VERSION 5.8 ;
BUSBITCHARS "[]" ;

UNITS
  DATABASE MICRONS 2000 ;
END UNITS

PROPERTYDEFINITIONS
  MACRO expanded_util REAL ;
END PROPERTYDEFINITIONS

LAYER OVERLAP
  TYPE OVERLAP ;
END OVERLAP

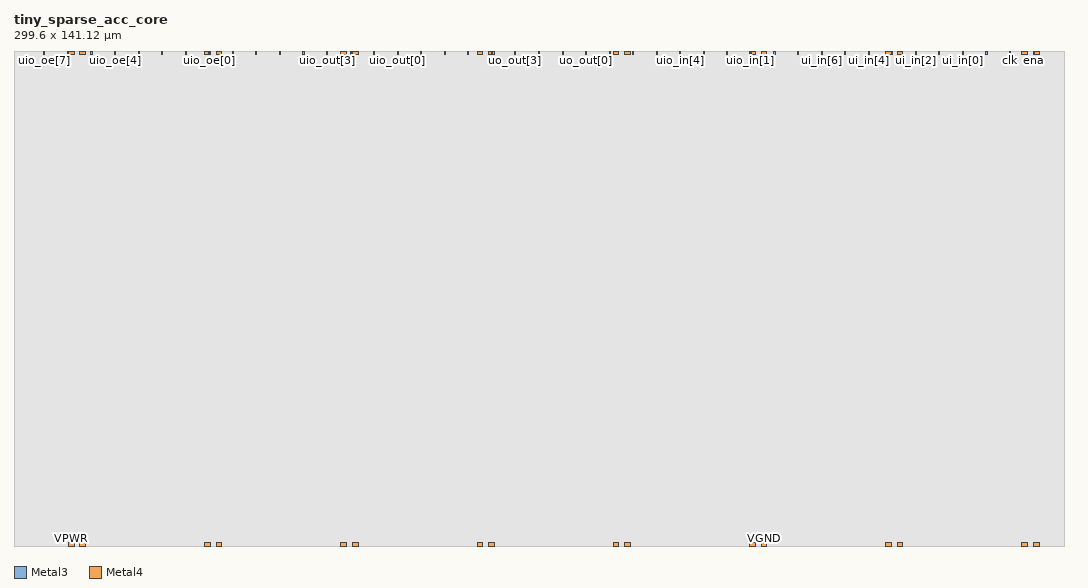
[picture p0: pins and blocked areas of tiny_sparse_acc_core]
MACRO tiny_sparse_acc_core
  CLASS BLOCK ;
  ORIGIN 0 0 ;
  SIZE 299.6 BY 141.12 ;
  SYMMETRY X Y ;
  PIN ui_in[7]
    DIRECTION INPUT ;
    USE SIGNAL ;
    PORT
      LAYER Metal3 ;
        RECT 223.57 140.12 223.87 141.12 ;
    END
  END ui_in[7]
  PIN ui_in[6]
    DIRECTION INPUT ;
    USE SIGNAL ;
    PORT
      LAYER Metal3 ;
        RECT 230.29 140.12 230.59 141.12 ;
    END
  END ui_in[6]
  PIN ui_in[5]
    DIRECTION INPUT ;
    USE SIGNAL ;
    PORT
      LAYER Metal3 ;
        RECT 237.01 140.12 237.31 141.12 ;
    END
  END ui_in[5]
  PIN ui_in[4]
    DIRECTION INPUT ;
    USE SIGNAL ;
    PORT
      LAYER Metal3 ;
        RECT 243.73 140.12 244.03 141.12 ;
    END
  END ui_in[4]
  PIN ui_in[3]
    DIRECTION INPUT ;
    USE SIGNAL ;
    PORT
      LAYER Metal3 ;
        RECT 250.45 140.12 250.75 141.12 ;
    END
  END ui_in[3]
  PIN ui_in[2]
    DIRECTION INPUT ;
    USE SIGNAL ;
    PORT
      LAYER Metal3 ;
        RECT 257.17 140.12 257.47 141.12 ;
    END
  END ui_in[2]
  PIN ui_in[1]
    DIRECTION INPUT ;
    USE SIGNAL ;
    PORT
      LAYER Metal3 ;
        RECT 263.89 140.12 264.19 141.12 ;
    END
  END ui_in[1]
  PIN ui_in[0]
    DIRECTION INPUT ;
    USE SIGNAL ;
    PORT
      LAYER Metal3 ;
        RECT 270.61 140.12 270.91 141.12 ;
    END
  END ui_in[0]
  PIN uo_out[7]
    DIRECTION OUTPUT ;
    USE SIGNAL ;
    PORT
      LAYER Metal3 ;
        RECT 116.05 140.12 116.35 141.12 ;
    END
  END uo_out[7]
  PIN uo_out[6]
    DIRECTION OUTPUT ;
    USE SIGNAL ;
    PORT
      LAYER Metal3 ;
        RECT 122.77 140.12 123.07 141.12 ;
    END
  END uo_out[6]
  PIN uo_out[5]
    DIRECTION OUTPUT ;
    USE SIGNAL ;
    PORT
      LAYER Metal3 ;
        RECT 129.49 140.12 129.79 141.12 ;
    END
  END uo_out[5]
  PIN uo_out[4]
    DIRECTION OUTPUT ;
    USE SIGNAL ;
    PORT
      LAYER Metal3 ;
        RECT 136.21 140.12 136.51 141.12 ;
    END
  END uo_out[4]
  PIN uo_out[3]
    DIRECTION OUTPUT ;
    USE SIGNAL ;
    PORT
      LAYER Metal3 ;
        RECT 142.93 140.12 143.23 141.12 ;
    END
  END uo_out[3]
  PIN uo_out[2]
    DIRECTION OUTPUT ;
    USE SIGNAL ;
    PORT
      LAYER Metal3 ;
        RECT 149.65 140.12 149.95 141.12 ;
    END
  END uo_out[2]
  PIN uo_out[1]
    DIRECTION OUTPUT ;
    USE SIGNAL ;
    PORT
      LAYER Metal3 ;
        RECT 156.37 140.12 156.67 141.12 ;
    END
  END uo_out[1]
  PIN uo_out[0]
    DIRECTION OUTPUT ;
    USE SIGNAL ;
    PORT
      LAYER Metal3 ;
        RECT 163.09 140.12 163.39 141.12 ;
    END
  END uo_out[0]
  PIN uio_in[7]
    DIRECTION INPUT ;
    USE SIGNAL ;
    PORT
      LAYER Metal3 ;
        RECT 169.81 140.12 170.11 141.12 ;
    END
  END uio_in[7]
  PIN uio_in[6]
    DIRECTION INPUT ;
    USE SIGNAL ;
    PORT
      LAYER Metal3 ;
        RECT 176.53 140.12 176.83 141.12 ;
    END
  END uio_in[6]
  PIN uio_in[5]
    DIRECTION INPUT ;
    USE SIGNAL ;
    PORT
      LAYER Metal3 ;
        RECT 183.25 140.12 183.55 141.12 ;
    END
  END uio_in[5]
  PIN uio_in[4]
    DIRECTION INPUT ;
    USE SIGNAL ;
    PORT
      LAYER Metal3 ;
        RECT 189.97 140.12 190.27 141.12 ;
    END
  END uio_in[4]
  PIN uio_in[3]
    DIRECTION INPUT ;
    USE SIGNAL ;
    PORT
      LAYER Metal3 ;
        RECT 196.69 140.12 196.99 141.12 ;
    END
  END uio_in[3]
  PIN uio_in[2]
    DIRECTION INPUT ;
    USE SIGNAL ;
    PORT
      LAYER Metal3 ;
        RECT 203.41 140.12 203.71 141.12 ;
    END
  END uio_in[2]
  PIN uio_in[1]
    DIRECTION INPUT ;
    USE SIGNAL ;
    PORT
      LAYER Metal3 ;
        RECT 210.13 140.12 210.43 141.12 ;
    END
  END uio_in[1]
  PIN uio_in[0]
    DIRECTION INPUT ;
    USE SIGNAL ;
    PORT
      LAYER Metal3 ;
        RECT 216.85 140.12 217.15 141.12 ;
    END
  END uio_in[0]
  PIN uio_out[7]
    DIRECTION OUTPUT ;
    USE SIGNAL ;
    PORT
      LAYER Metal3 ;
        RECT 62.29 140.12 62.59 141.12 ;
    END
  END uio_out[7]
  PIN uio_out[6]
    DIRECTION OUTPUT ;
    USE SIGNAL ;
    PORT
      LAYER Metal3 ;
        RECT 69.01 140.12 69.31 141.12 ;
    END
  END uio_out[6]
  PIN uio_out[5]
    DIRECTION OUTPUT ;
    USE SIGNAL ;
    PORT
      LAYER Metal3 ;
        RECT 75.73 140.12 76.03 141.12 ;
    END
  END uio_out[5]
  PIN uio_out[4]
    DIRECTION OUTPUT ;
    USE SIGNAL ;
    PORT
      LAYER Metal3 ;
        RECT 82.45 140.12 82.75 141.12 ;
    END
  END uio_out[4]
  PIN uio_out[3]
    DIRECTION OUTPUT ;
    USE SIGNAL ;
    PORT
      LAYER Metal3 ;
        RECT 89.17 140.12 89.47 141.12 ;
    END
  END uio_out[3]
  PIN uio_out[2]
    DIRECTION OUTPUT ;
    USE SIGNAL ;
    PORT
      LAYER Metal3 ;
        RECT 95.89 140.12 96.19 141.12 ;
    END
  END uio_out[2]
  PIN uio_out[1]
    DIRECTION OUTPUT ;
    USE SIGNAL ;
    PORT
      LAYER Metal3 ;
        RECT 102.61 140.12 102.91 141.12 ;
    END
  END uio_out[1]
  PIN uio_out[0]
    DIRECTION OUTPUT ;
    USE SIGNAL ;
    PORT
      LAYER Metal3 ;
        RECT 109.33 140.12 109.63 141.12 ;
    END
  END uio_out[0]
  PIN uio_oe[7]
    DIRECTION OUTPUT ;
    USE SIGNAL ;
    PORT
      LAYER Metal3 ;
        RECT 8.53 140.12 8.83 141.12 ;
    END
  END uio_oe[7]
  PIN uio_oe[6]
    DIRECTION OUTPUT ;
    USE SIGNAL ;
    PORT
      LAYER Metal3 ;
        RECT 15.25 140.12 15.55 141.12 ;
    END
  END uio_oe[6]
  PIN uio_oe[5]
    DIRECTION OUTPUT ;
    USE SIGNAL ;
    PORT
      LAYER Metal3 ;
        RECT 21.97 140.12 22.27 141.12 ;
    END
  END uio_oe[5]
  PIN uio_oe[4]
    DIRECTION OUTPUT ;
    USE SIGNAL ;
    PORT
      LAYER Metal3 ;
        RECT 28.69 140.12 28.99 141.12 ;
    END
  END uio_oe[4]
  PIN uio_oe[3]
    DIRECTION OUTPUT ;
    USE SIGNAL ;
    PORT
      LAYER Metal3 ;
        RECT 35.41 140.12 35.71 141.12 ;
    END
  END uio_oe[3]
  PIN uio_oe[2]
    DIRECTION OUTPUT ;
    USE SIGNAL ;
    PORT
      LAYER Metal3 ;
        RECT 42.13 140.12 42.43 141.12 ;
    END
  END uio_oe[2]
  PIN uio_oe[1]
    DIRECTION OUTPUT ;
    USE SIGNAL ;
    PORT
      LAYER Metal3 ;
        RECT 48.85 140.12 49.15 141.12 ;
    END
  END uio_oe[1]
  PIN uio_oe[0]
    DIRECTION OUTPUT ;
    USE SIGNAL ;
    PORT
      LAYER Metal3 ;
        RECT 55.57 140.12 55.87 141.12 ;
    END
  END uio_oe[0]
  PIN ena
    DIRECTION INPUT ;
    USE SIGNAL ;
    PORT
      LAYER Metal3 ;
        RECT 290.77 140.12 291.07 141.12 ;
    END
  END ena
  PIN clk
    DIRECTION INPUT ;
    USE CLOCK ;
    PORT
      LAYER Metal3 ;
        RECT 284.05 140.12 284.35 141.12 ;
    END
  END clk
  PIN rst_n
    DIRECTION INPUT ;
    USE SIGNAL ;
    PORT
      LAYER Metal3 ;
        RECT 277.33 140.12 277.63 141.12 ;
    END
  END rst_n
  PIN VPWR
    DIRECTION INOUT ;
    USE POWER ;
    PORT
      LAYER Metal4 ;
        RECT 15.52 0 17.12 1 ;
        RECT 54.39 0 55.99 1 ;
        RECT 93.26 0 94.86 1 ;
        RECT 132.13 0 133.73 1 ;
        RECT 171 0 172.6 1 ;
        RECT 209.87 0 211.47 1 ;
        RECT 248.74 0 250.34 1 ;
        RECT 287.61 0 289.21 1 ;
        RECT 15.52 140.12 17.12 141.12 ;
        RECT 54.39 140.12 55.99 141.12 ;
        RECT 93.26 140.12 94.86 141.12 ;
        RECT 132.13 140.12 133.73 141.12 ;
        RECT 171 140.12 172.6 141.12 ;
        RECT 209.87 140.12 211.47 141.12 ;
        RECT 248.74 140.12 250.34 141.12 ;
        RECT 287.61 140.12 289.21 141.12 ;
    END
  END VPWR
  PIN VGND
    DIRECTION INOUT ;
    USE GROUND ;
    PORT
      LAYER Metal4 ;
        RECT 18.82 0 20.42 1 ;
        RECT 57.69 0 59.29 1 ;
        RECT 96.56 0 98.16 1 ;
        RECT 135.43 0 137.03 1 ;
        RECT 174.3 0 175.9 1 ;
        RECT 213.17 0 214.77 1 ;
        RECT 252.04 0 253.64 1 ;
        RECT 290.91 0 292.51 1 ;
        RECT 18.82 140.12 20.42 141.12 ;
        RECT 57.69 140.12 59.29 141.12 ;
        RECT 96.56 140.12 98.16 141.12 ;
        RECT 135.43 140.12 137.03 141.12 ;
        RECT 174.3 140.12 175.9 141.12 ;
        RECT 213.17 140.12 214.77 141.12 ;
        RECT 252.04 140.12 253.64 141.12 ;
        RECT 290.91 140.12 292.51 141.12 ;
    END
  END VGND
  OBS
    LAYER Metal1 SPACING 0 ;
      RECT 0 0 299.6 141.12 ;
    LAYER Metal2 SPACING 0 ;
      RECT 0 0 299.6 141.12 ;
    LAYER Metal3 SPACING 0 ;
      POLYGON 299.6 141.12 299.6 0 0 0 0 141.12 8.53 141.12 8.53 140.12 8.83 140.12 8.83 141.12 15.25 141.12 15.25 140.12 15.55 140.12 15.55 141.12 21.97 141.12 21.97 140.12 22.27 140.12 22.27 141.12 28.69 141.12 28.69 140.12 28.99 140.12 28.99 141.12 35.41 141.12 35.41 140.12 35.71 140.12 35.71 141.12 42.13 141.12 42.13 140.12 42.43 140.12 42.43 141.12 48.85 141.12 48.85 140.12 49.15 140.12 49.15 141.12 55.57 141.12 55.57 140.12 55.87 140.12 55.87 141.12 62.29 141.12 62.29 140.12 62.59 140.12 62.59 141.12 69.01 141.12 69.01 140.12 69.31 140.12 69.31 141.12 75.73 141.12 75.73 140.12 76.03 140.12 76.03 141.12 82.45 141.12 82.45 140.12 82.75 140.12 82.75 141.12 89.17 141.12 89.17 140.12 89.47 140.12 89.47 141.12 95.89 141.12 95.89 140.12 96.19 140.12 96.19 141.12 102.61 141.12 102.61 140.12 102.91 140.12 102.91 141.12 109.33 141.12 109.33 140.12 109.63 140.12 109.63 141.12 116.05 141.12 116.05 140.12 116.35 140.12 116.35 141.12 122.77 141.12 122.77 140.12 123.07 140.12 123.07 141.12 129.49 141.12 129.49 140.12 129.79 140.12 129.79 141.12 136.21 141.12 136.21 140.12 136.51 140.12 136.51 141.12 142.93 141.12 142.93 140.12 143.23 140.12 143.23 141.12 149.65 141.12 149.65 140.12 149.95 140.12 149.95 141.12 156.37 141.12 156.37 140.12 156.67 140.12 156.67 141.12 163.09 141.12 163.09 140.12 163.39 140.12 163.39 141.12 169.81 141.12 169.81 140.12 170.11 140.12 170.11 141.12 176.53 141.12 176.53 140.12 176.83 140.12 176.83 141.12 183.25 141.12 183.25 140.12 183.55 140.12 183.55 141.12 189.97 141.12 189.97 140.12 190.27 140.12 190.27 141.12 196.69 141.12 196.69 140.12 196.99 140.12 196.99 141.12 203.41 141.12 203.41 140.12 203.71 140.12 203.71 141.12 210.13 141.12 210.13 140.12 210.43 140.12 210.43 141.12 216.85 141.12 216.85 140.12 217.15 140.12 217.15 141.12 223.57 141.12 223.57 140.12 223.87 140.12 223.87 141.12 230.29 141.12 230.29 140.12 230.59 140.12 230.59 141.12 237.01 141.12 237.01 140.12 237.31 140.12 237.31 141.12 243.73 141.12 243.73 140.12 244.03 140.12 244.03 141.12 250.45 141.12 250.45 140.12 250.75 140.12 250.75 141.12 257.17 141.12 257.17 140.12 257.47 140.12 257.47 141.12 263.89 141.12 263.89 140.12 264.19 140.12 264.19 141.12 270.61 141.12 270.61 140.12 270.91 140.12 270.91 141.12 277.33 141.12 277.33 140.12 277.63 140.12 277.63 141.12 284.05 141.12 284.05 140.12 284.35 140.12 284.35 141.12 290.77 141.12 290.77 140.12 291.07 140.12 291.07 141.12 ;
    LAYER Metal4 SPACING 0 ;
      POLYGON 299.6 141.12 299.6 0 292.51 0 292.51 1 290.91 1 290.91 0 289.21 0 289.21 1 287.61 1 287.61 0 253.64 0 253.64 1 252.04 1 252.04 0 250.34 0 250.34 1 248.74 1 248.74 0 214.77 0 214.77 1 213.17 1 213.17 0 211.47 0 211.47 1 209.87 1 209.87 0 175.9 0 175.9 1 174.3 1 174.3 0 172.6 0 172.6 1 171 1 171 0 137.03 0 137.03 1 135.43 1 135.43 0 133.73 0 133.73 1 132.13 1 132.13 0 98.16 0 98.16 1 96.56 1 96.56 0 94.86 0 94.86 1 93.26 1 93.26 0 59.29 0 59.29 1 57.69 1 57.69 0 55.99 0 55.99 1 54.39 1 54.39 0 20.42 0 20.42 1 18.82 1 18.82 0 17.12 0 17.12 1 15.52 1 15.52 0 0 0 0 141.12 15.52 141.12 15.52 140.12 17.12 140.12 17.12 141.12 18.82 141.12 18.82 140.12 20.42 140.12 20.42 141.12 54.39 141.12 54.39 140.12 55.99 140.12 55.99 141.12 57.69 141.12 57.69 140.12 59.29 140.12 59.29 141.12 93.26 141.12 93.26 140.12 94.86 140.12 94.86 141.12 96.56 141.12 96.56 140.12 98.16 140.12 98.16 141.12 132.13 141.12 132.13 140.12 133.73 140.12 133.73 141.12 135.43 141.12 135.43 140.12 137.03 140.12 137.03 141.12 171 141.12 171 140.12 172.6 140.12 172.6 141.12 174.3 141.12 174.3 140.12 175.9 140.12 175.9 141.12 209.87 141.12 209.87 140.12 211.47 140.12 211.47 141.12 213.17 141.12 213.17 140.12 214.77 140.12 214.77 141.12 248.74 141.12 248.74 140.12 250.34 140.12 250.34 141.12 252.04 141.12 252.04 140.12 253.64 140.12 253.64 141.12 287.61 141.12 287.61 140.12 289.21 140.12 289.21 141.12 290.91 141.12 290.91 140.12 292.51 140.12 292.51 141.12 ;
    LAYER Metal3 ;
      POLYGON 299.3 140.82 299.3 0.3 0.3 0.3 0.3 140.82 8.23 140.82 8.23 139.82 9.13 139.82 9.13 140.82 14.95 140.82 14.95 139.82 15.85 139.82 15.85 140.82 21.67 140.82 21.67 139.82 22.57 139.82 22.57 140.82 28.39 140.82 28.39 139.82 29.29 139.82 29.29 140.82 35.11 140.82 35.11 139.82 36.01 139.82 36.01 140.82 41.83 140.82 41.83 139.82 42.73 139.82 42.73 140.82 48.55 140.82 48.55 139.82 49.45 139.82 49.45 140.82 55.27 140.82 55.27 139.82 56.17 139.82 56.17 140.82 61.99 140.82 61.99 139.82 62.89 139.82 62.89 140.82 68.71 140.82 68.71 139.82 69.61 139.82 69.61 140.82 75.43 140.82 75.43 139.82 76.33 139.82 76.33 140.82 82.15 140.82 82.15 139.82 83.05 139.82 83.05 140.82 88.87 140.82 88.87 139.82 89.77 139.82 89.77 140.82 95.59 140.82 95.59 139.82 96.49 139.82 96.49 140.82 102.31 140.82 102.31 139.82 103.21 139.82 103.21 140.82 109.03 140.82 109.03 139.82 109.93 139.82 109.93 140.82 115.75 140.82 115.75 139.82 116.65 139.82 116.65 140.82 122.47 140.82 122.47 139.82 123.37 139.82 123.37 140.82 129.19 140.82 129.19 139.82 130.09 139.82 130.09 140.82 135.91 140.82 135.91 139.82 136.81 139.82 136.81 140.82 142.63 140.82 142.63 139.82 143.53 139.82 143.53 140.82 149.35 140.82 149.35 139.82 150.25 139.82 150.25 140.82 156.07 140.82 156.07 139.82 156.97 139.82 156.97 140.82 162.79 140.82 162.79 139.82 163.69 139.82 163.69 140.82 169.51 140.82 169.51 139.82 170.41 139.82 170.41 140.82 176.23 140.82 176.23 139.82 177.13 139.82 177.13 140.82 182.95 140.82 182.95 139.82 183.85 139.82 183.85 140.82 189.67 140.82 189.67 139.82 190.57 139.82 190.57 140.82 196.39 140.82 196.39 139.82 197.29 139.82 197.29 140.82 203.11 140.82 203.11 139.82 204.01 139.82 204.01 140.82 209.83 140.82 209.83 139.82 210.73 139.82 210.73 140.82 216.55 140.82 216.55 139.82 217.45 139.82 217.45 140.82 223.27 140.82 223.27 139.82 224.17 139.82 224.17 140.82 229.99 140.82 229.99 139.82 230.89 139.82 230.89 140.82 236.71 140.82 236.71 139.82 237.61 139.82 237.61 140.82 243.43 140.82 243.43 139.82 244.33 139.82 244.33 140.82 250.15 140.82 250.15 139.82 251.05 139.82 251.05 140.82 256.87 140.82 256.87 139.82 257.77 139.82 257.77 140.82 263.59 140.82 263.59 139.82 264.49 139.82 264.49 140.82 270.31 140.82 270.31 139.82 271.21 139.82 271.21 140.82 277.03 140.82 277.03 139.82 277.93 139.82 277.93 140.82 283.75 140.82 283.75 139.82 284.65 139.82 284.65 140.82 290.47 140.82 290.47 139.82 291.37 139.82 291.37 140.82 ;
    LAYER Metal4 ;
      POLYGON 299.3 140.82 299.3 0.3 292.81 0.3 292.81 1.3 290.61 1.3 290.61 0.3 289.51 0.3 289.51 1.3 287.31 1.3 287.31 0.3 253.94 0.3 253.94 1.3 251.74 1.3 251.74 0.3 250.64 0.3 250.64 1.3 248.44 1.3 248.44 0.3 215.07 0.3 215.07 1.3 212.87 1.3 212.87 0.3 211.77 0.3 211.77 1.3 209.57 1.3 209.57 0.3 176.2 0.3 176.2 1.3 174 1.3 174 0.3 172.9 0.3 172.9 1.3 170.7 1.3 170.7 0.3 137.33 0.3 137.33 1.3 135.13 1.3 135.13 0.3 134.03 0.3 134.03 1.3 131.83 1.3 131.83 0.3 98.46 0.3 98.46 1.3 96.26 1.3 96.26 0.3 95.16 0.3 95.16 1.3 92.96 1.3 92.96 0.3 59.59 0.3 59.59 1.3 57.39 1.3 57.39 0.3 56.29 0.3 56.29 1.3 54.09 1.3 54.09 0.3 20.72 0.3 20.72 1.3 18.52 1.3 18.52 0.3 17.42 0.3 17.42 1.3 15.22 1.3 15.22 0.3 0.3 0.3 0.3 140.82 15.22 140.82 15.22 139.82 17.42 139.82 17.42 140.82 18.52 140.82 18.52 139.82 20.72 139.82 20.72 140.82 54.09 140.82 54.09 139.82 56.29 139.82 56.29 140.82 57.39 140.82 57.39 139.82 59.59 139.82 59.59 140.82 92.96 140.82 92.96 139.82 95.16 139.82 95.16 140.82 96.26 140.82 96.26 139.82 98.46 139.82 98.46 140.82 131.83 140.82 131.83 139.82 134.03 139.82 134.03 140.82 135.13 140.82 135.13 139.82 137.33 139.82 137.33 140.82 170.7 140.82 170.7 139.82 172.9 139.82 172.9 140.82 174 140.82 174 139.82 176.2 139.82 176.2 140.82 209.57 140.82 209.57 139.82 211.77 139.82 211.77 140.82 212.87 140.82 212.87 139.82 215.07 139.82 215.07 140.82 248.44 140.82 248.44 139.82 250.64 139.82 250.64 140.82 251.74 140.82 251.74 139.82 253.94 139.82 253.94 140.82 287.31 140.82 287.31 139.82 289.51 139.82 289.51 140.82 290.61 140.82 290.61 139.82 292.81 139.82 292.81 140.82 ;
    LAYER Metal1 ;
      RECT 0.3 0.3 299.3 140.82 ;
    LAYER Metal2 ;
      RECT 0.3 0.3 299.3 140.82 ;
    LAYER Via2 ;
      RECT 14.99 140.43 15.25 140.69 ;
      RECT 149.39 139.87 149.65 140.13 ;
      RECT 82.19 139.87 82.45 140.13 ;
    LAYER Via3 ;
      RECT 277.07 140.43 277.33 140.69 ;
      RECT 203.15 140.43 203.41 140.69 ;
      RECT 102.35 140.43 102.61 140.69 ;
      RECT 69.31 140.43 69.57 140.69 ;
      RECT 28.43 140.43 28.69 140.69 ;
    LAYER OVERLAP ;
      POLYGON 0 0 0 141.12 299.6 141.12 299.6 0 ;
  END
  PROPERTY expanded_util 0.845 ;
END tiny_sparse_acc_core

END LIBRARY
